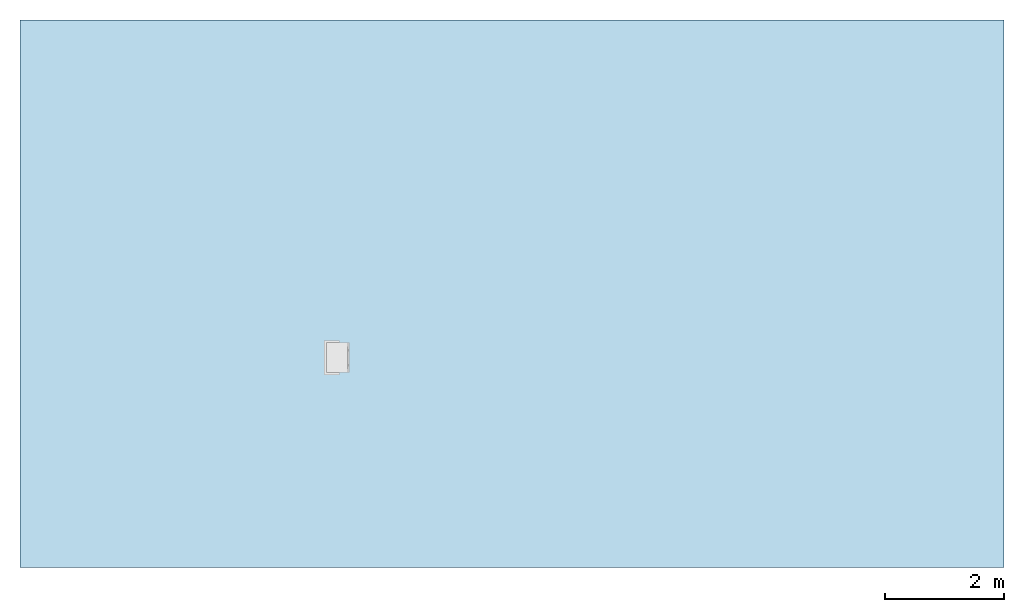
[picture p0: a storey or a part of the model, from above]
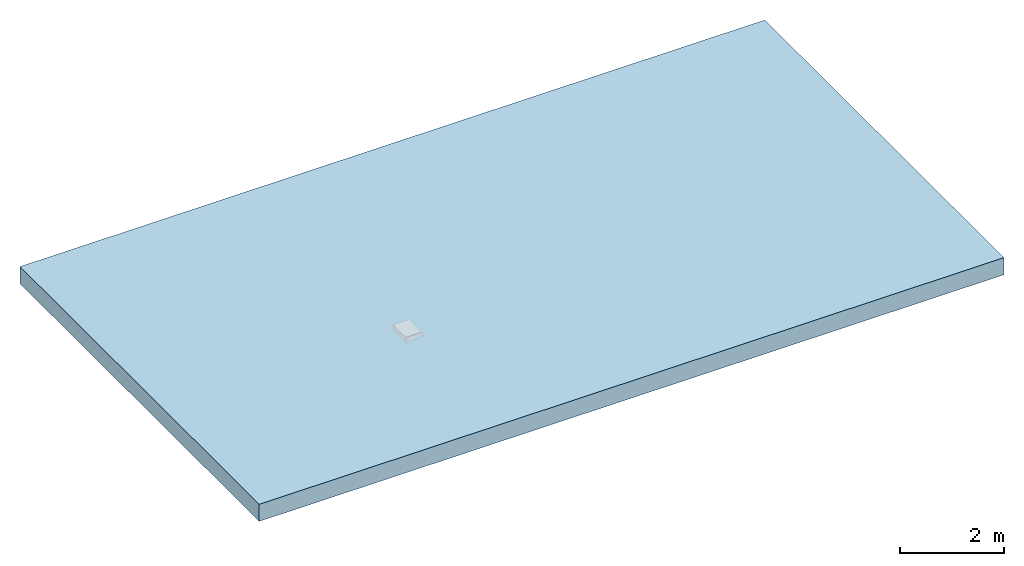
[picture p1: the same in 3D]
Properties of the parts of a building model (IFC2X3)

# File
Description: ViewDefinition [CoordinationView]
File name: 4928 - Top assembly KDG.ifc
Time: 2013-09-04T09:38:00
Written by: Autodesk Revit 2013
Made in: 20120221_2030(x64)

# IfcProject, Project Number
LongName: Project Name; Phase: Project Status

# IfcSite, Default
RefLatitude: 42, 21, 30, 344238; RefLongitude: -71, -3, -35, -194702; RefElevation: 0 mm

# IfcBuilding
Pset_BuildingCommon - NumberOfStoreys: 1
Other - Project Number: Project Number; Project Issue Date: Issue Date; Client Name: Owner; Project Address: ## Street City, State Zip; Project Name: Project Name; Project Status: Project Status

# IfcBuildingStorey, Level 1
LongName: Level 1; Elevation: 0 mm
Constraints - Elevation Base: 0; Elevation: 0 mm
Graphics - Line Weight: 1; Symbol at End 2 Default: yes; Symbol at End 1 Default: no; Symbol: M_Level Head - Circle: M_Level Head - Circle; Color: 0; Line Pattern: Center
Identity Data - Structural: no; Name: Level 1; Building Story: yes
Dimensions - Computation Height: 0 mm

# IfcBuildingElementProxy: 4928 - Top assembly KDG, Civil-Drainage-Channel-ACO-KerbDrain-HB Gully units:4928 - Top assembly KDG:4928 - Top assembly KDG:309626
In: Level 1
Material: Cast Iron, ACO Polmer Concrete., Gully Colour
Constraints - Level: Level: Level 1; Moves With Nearby Elements: no
Dimensions - Volume: 19548807 mm3; Gully Connector Void Start: 2000 mm; Deep Base Void Depth: 6000 mm; Shallow Base Depth: 6000 mm; Gully Connector Void End: 2005 mm; Top and bottom 4979 void depth: 6000 mm
Phasing - Phase Created: New Construction
Pset_BuildingElementProxyCommon - Reference: 4928 - Top assembly KDG
Identity Data - Manufacturer: ACO Technologies plc - ACO Water Management Division; Cost: 0; Telephone: +44 (0)1462 816666; Product Code: 4928; Price: POA - contact ACO; Assembly Description: Rain Water Drainage; Product Page URL: http://www.aco.co.uk/product_detail.php?id=3; OmniClass Number: 23.70.50.24; e-mail Sales: customersupport@aco.co.uk; URL: www.aco.co.uk; Model Description: Combined kerb and drainage system; Product brochure: http://www.aco.co.uk/download.php?id=120; Model: ACO KerbDrain Half Battered Gully Units; Maintenance guidelines: http://www.aco.co.uk/download.php?id=120; OmniClass Title: Rainwater Removal; Address: ACO Business Park, Hitchin Road, Shefford, Bedfordshire, United Kingdom SG17 5TE; e-mail Technical: technical@aco.co.uk; Assembly Code: D2040; Fax: +44 (0)1462 815895; Type Comments: ACO KerbDrain Half Battered Gully Units - Top Assembly KDG; Installation guidelines: http://www.aco.co.uk/download.php?id=120
Data - Invert Depth: N/A; Product Weight: 76.8 Kg; ACO Hydraulic Design Software: http://www.acodesign.co.uk; Product Dimensions: 500mm x 390mm x 520mm (LxWxH); Drainage Slot Intake area: 14592mm²/m; Load Class: A 15 - D 400; Drainage Slot Width: 50mm; Product Standard: BS EN 1433:2002, CE marked, Kitemarked; Hydraulic Performance: http://www.aco.co.uk/download.php?id=120; Installation - Concrete Grade: Refer to brochure
Materials and Finishes - Gully Cover/Frame Finish: Water Based Paint Coating; Gully Cover/Frame Material: Ductile Iron; Gully Base Colour: Brown; Gully Cover/Frame Colour: Black; Gully Base Material: Vienite® Synthetic Resin Concrete
General - TagNumber: 0.000000; SerialNumber: 0.000000
Other - CreatedBy: www.aco.co.uk; Revision: 1
Construction - Top assembly: yes; Top and roddable deep base assembly KD612RE: no; Shallow base: no; Deep Base: no; Top and road gully connector: no
Green Building Properties - Gully Base Recycled Material Content: 20% minimum; Gully Cover/Frame Recycled Material Content: Between 40% - 90%; Gully Base Recyclable: Fully recyclable; Gully Cover/Frame Recyclable: Fully recyclable

# IfcOpeningElement: Recess (3)
In: Level 1
Dimensions - Volume: 60510560964 mm3; Thickness: 400 mm; Area: 151470000 mm2; Perimeter: 51360 mm
Constraints - Height Offset From Level: 0 mm; Room Bounding: yes; Related to Mass: no; Level: Level: Level 1
Phasing - Phase Created: New Construction
Structural - Structural: no; Enable Analytical Model: no
Analytical Properties - Roughness: 1; Absorptance: 0.1
Graphics - Coarse Scale Fill Color: 0
Construction - Function: 0; Default Thickness: 400 mm
Materials and Finishes - Structural Material: Plant

# IfcSlab: Floor:Generic Floor - 400mm, Floor:Generic Floor - 400mm:193825
In: Level 1
PredefinedType: FLOOR; Material: Plant 400 mm
Dimensions - Volume: 60510560964 mm3; Thickness: 400 mm; Area: 151470000 mm2; Perimeter: 51360 mm
Constraints - Height Offset From Level: 0 mm; Room Bounding: yes; Related to Mass: no; Level: Level: Level 1
Phasing - Phase Created: New Construction
Structural - Structural: no; Enable Analytical Model: no
Pset_SlabCommon - Reference: Generic Floor - 400mm; IsExternal: no; LoadBearing: yes
Analytical Properties - Roughness: 1; Absorptance: 0.1
Graphics - Coarse Scale Fill Color: 0
Construction - Function: 0; Default Thickness: 400 mm
Materials and Finishes - Structural Material: Plant
